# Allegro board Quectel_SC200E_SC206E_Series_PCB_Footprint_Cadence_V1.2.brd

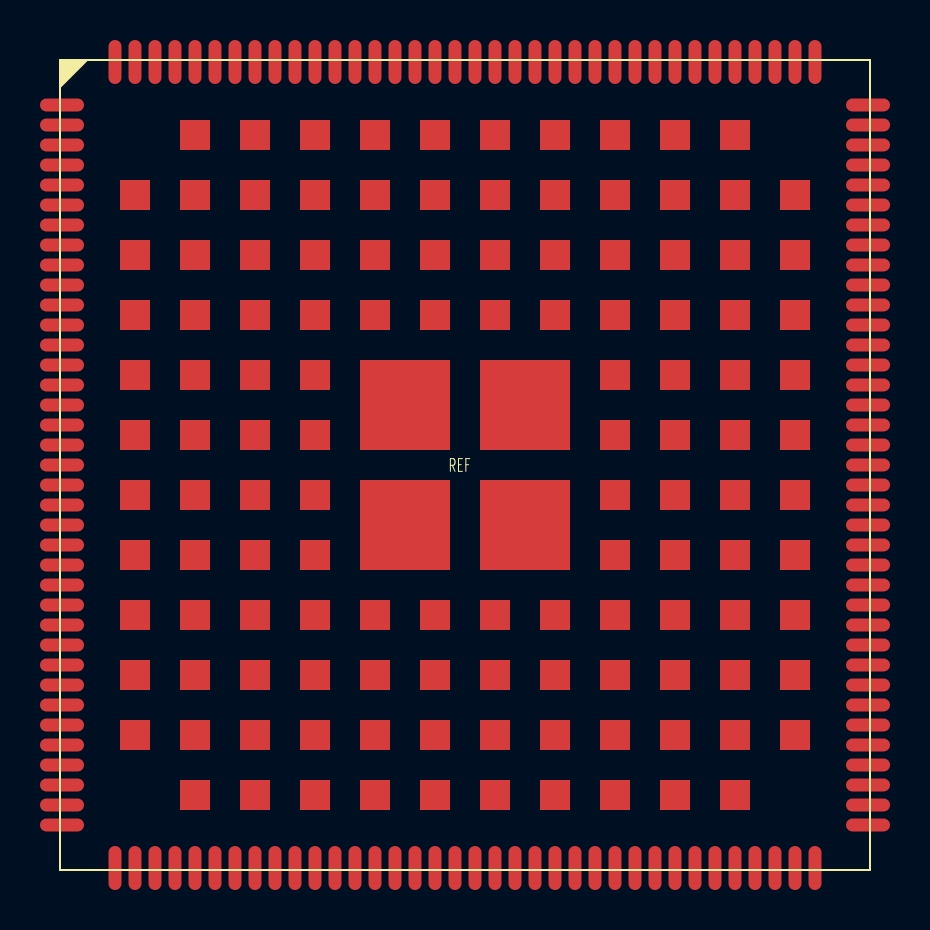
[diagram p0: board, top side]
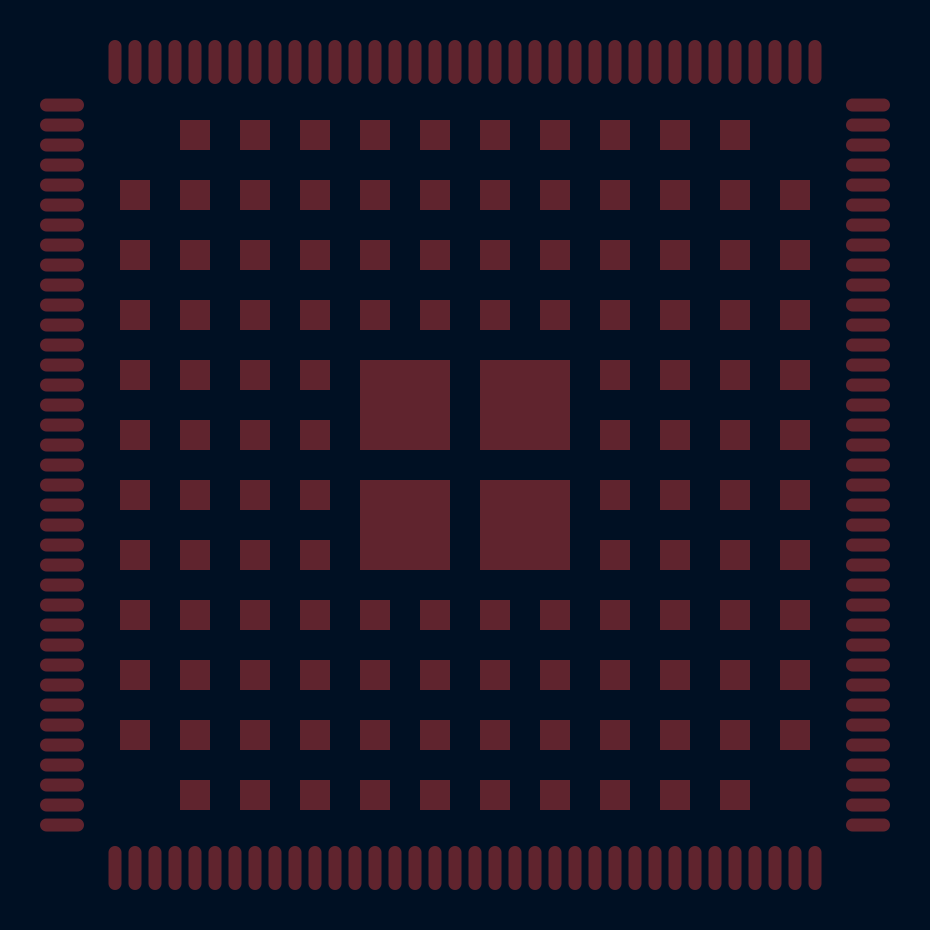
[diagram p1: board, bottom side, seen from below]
No outline. copper layers: TOP, INNER LAYER 2, INNER LAYER 3, BOTTOM. Coordinates in mm from the lowest, leftmost part position.

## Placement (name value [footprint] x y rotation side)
REF  -  [unnamed]  0 0 0 top

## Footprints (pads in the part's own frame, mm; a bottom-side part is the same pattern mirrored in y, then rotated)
unnamed
  oval 2.2x0.65 smd: 1(-20.15,18) 2(-20.15,17) 3(-20.15,16) 4(-20.15,15) 5(-20.15,14) 6(-20.15,13) 7(-20.15,12) 8(-20.15,11) 9(-20.15,10) 10(-20.15,9) 11(-20.15,8) 12(-20.15,7) 13(-20.15,6) 14(-20.15,5) 15(-20.15,4) 16(-20.15,3) 17(-20.15,2) 18(-20.15,1) 19(-20.15,0) 20(-20.15,-1) 21(-20.15,-2) 22(-20.15,-3) 23(-20.15,-4) 24(-20.15,-5) 25(-20.15,-6) 26(-20.15,-7) 27(-20.15,-8) 28(-20.15,-9) 29(-20.15,-10) 30(-20.15,-11) 31(-20.15,-12) 32(-20.15,-13) 33(-20.15,-14) 34(-20.15,-15) 35(-20.15,-16) 36(-20.15,-17) 37(-20.15,-18) 74(20.15,-18) 75(20.15,-17) 76(20.15,-16) 77(20.15,-15) 78(20.15,-14) 79(20.15,-13) 80(20.15,-12) 81(20.15,-11) 82(20.15,-10) 83(20.15,-9) 84(20.15,-8) 85(20.15,-7) 86(20.15,-6) 87(20.15,-5) 88(20.15,-4) 89(20.15,-3) 90(20.15,-2) 91(20.15,-1) 92(20.15,0) 93(20.15,1) 94(20.15,2) 95(20.15,3) 96(20.15,4) 97(20.15,5) 98(20.15,6) 99(20.15,7) 100(20.15,8) 101(20.15,9) 102(20.15,10) 103(20.15,11) 104(20.15,12) 105(20.15,13) 106(20.15,14) 107(20.15,15) 108(20.15,16) 109(20.15,17) 110(20.15,18)
  oval 0.65x2.2 smd: 38(-17.5,-20.15) 39(-16.5,-20.15) 40(-15.5,-20.15) 41(-14.5,-20.15) 42(-13.5,-20.15) 43(-12.5,-20.15) 44(-11.5,-20.15) 45(-10.5,-20.15) 46(-9.5,-20.15) 47(-8.5,-20.15) 48(-7.5,-20.15) 49(-6.5,-20.15) 50(-5.5,-20.15) 51(-4.5,-20.15) 52(-3.5,-20.15) 53(-2.5,-20.15) 54(-1.5,-20.15) 55(-0.5,-20.15) 56(0.5,-20.15) 57(1.5,-20.15) 58(2.5,-20.15) 59(3.5,-20.15) 60(4.5,-20.15) 61(5.5,-20.15) 62(6.5,-20.15) 63(7.5,-20.15) 64(8.5,-20.15) 65(9.5,-20.15) 66(10.5,-20.15) 67(11.5,-20.15) 68(12.5,-20.15) 69(13.5,-20.15) 70(14.5,-20.15) 71(15.5,-20.15) 72(16.5,-20.15) 73(17.5,-20.15) 111(17.5,20.15) 112(16.5,20.15) 113(15.5,20.15) 114(14.5,20.15) 115(13.5,20.15) 116(12.5,20.15) 117(11.5,20.15) 118(10.5,20.15) 119(9.5,20.15) 120(8.5,20.15) 121(7.5,20.15) 122(6.5,20.15) 123(5.5,20.15) 124(4.5,20.15) 125(3.5,20.15) 126(2.5,20.15) 127(1.5,20.15) 128(0.5,20.15) 129(-0.5,20.15) 130(-1.5,20.15) 131(-2.5,20.15) 132(-3.5,20.15) 133(-4.5,20.15) 134(-5.5,20.15) 135(-6.5,20.15) 136(-7.5,20.15) 137(-8.5,20.15) 138(-9.5,20.15) 139(-10.5,20.15) 140(-11.5,20.15) 141(-12.5,20.15) 142(-13.5,20.15) 143(-14.5,20.15) 144(-15.5,20.15) 145(-16.5,20.15) 146(-17.5,20.15)
  rect 1.5x1.5 smd: 147(-16.5,13.5) 148(-16.5,10.5) 149(-16.5,7.5) 150(-16.5,4.5) 151(-16.5,1.5) 152(-16.5,-1.5) 153(-16.5,-4.5) 154(-16.5,-7.5) 155(-16.5,-10.5) 156(-16.5,-13.5) 157(-13.5,-16.5) 158(-10.5,-16.5) 159(-7.5,-16.5) 160(-4.5,-16.5) 161(-1.5,-16.5) 162(1.5,-16.5) 163(4.5,-16.5) 164(7.5,-16.5) 165(10.5,-16.5) 166(13.5,-16.5) 167(16.5,-13.5) 168(16.5,-10.5) 169(16.5,-7.5) 170(16.5,-4.5) 171(16.5,-1.5) 172(16.5,1.5) 173(16.5,4.5) 174(16.5,7.5) 175(16.5,10.5) 176(16.5,13.5) 177(13.5,16.5) 178(10.5,16.5) 179(7.5,16.5) 180(4.5,16.5) 181(1.5,16.5) 182(-1.5,16.5) 183(-4.5,16.5) 184(-7.5,16.5) 185(-10.5,16.5) 186(-13.5,16.5) 187(-13.5,13.5) 188(-13.5,10.5) 189(-13.5,7.5) 190(-13.5,4.5) 191(-13.5,1.5) 192(-13.5,-1.5) 193(-13.5,-4.5) 194(-13.5,-7.5) 195(-13.5,-10.5) 196(-13.5,-13.5) 197(-10.5,-13.5) 198(-7.5,-13.5) 199(-4.5,-13.5) 200(-1.5,-13.5) 201(1.5,-13.5) 202(4.5,-13.5) 203(7.5,-13.5) 204(10.5,-13.5) 205(13.5,-13.5) 206(13.5,-10.5) 207(13.5,-7.5) 208(13.5,-4.5) 209(13.5,-1.5) 210(13.5,1.5) 211(13.5,4.5) 212(13.5,7.5) 213(13.5,10.5) 214(13.5,13.5) 215(10.5,13.5) 216(7.5,13.5) 217(4.5,13.5) 218(1.5,13.5) 219(-1.5,13.5) 220(-4.5,13.5) 221(-7.5,13.5) 222(-10.5,13.5) 223(-10.5,10.5) 224(-10.5,7.5) 225(-10.5,4.5) 226(-10.5,1.5) 227(-10.5,-1.5) 228(-10.5,-4.5) 229(-10.5,-7.5) 230(-10.5,-10.5) 231(-7.5,-10.5) 232(-4.5,-10.5) 233(-1.5,-10.5) 234(1.5,-10.5) 235(4.5,-10.5) 236(7.5,-10.5) 237(10.5,-10.5) 238(10.5,-7.5) 239(10.5,-4.5) 240(10.5,-1.5) 241(10.5,1.5) 242(10.5,4.5) 243(10.5,7.5) 244(10.5,10.5) 245(7.5,10.5) 246(4.5,10.5) 247(1.5,10.5) 248(-1.5,10.5) 249(-4.5,10.5) 250(-7.5,10.5) 251(-7.5,7.5) 252(-7.5,4.5) 253(-7.5,1.5) 254(-7.5,-1.5) 255(-7.5,-4.5) 256(-7.5,-7.5) 257(-4.5,-7.5) 258(-1.5,-7.5) 259(1.5,-7.5) 260(4.5,-7.5) 261(7.5,-7.5) 262(7.5,-4.5) 263(7.5,-1.5) 264(7.5,1.5) 265(7.5,4.5) 266(7.5,7.5) 267(4.5,7.5) 268(1.5,7.5) 269(-1.5,7.5) 270(-4.5,7.5)
  rect 4.5x4.5 smd: 271(-3,3) 272(-3,-3) 273(3,-3) 274(3,3)

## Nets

Pads without a net: REF 1 2 3 4 5 6 7 8 9 10 11 12 13 14 15 16 17 18 19 20 21 22 23 24 25 26 27 28 29 30 31 32 33 34 35 36 37 38 39 40 41 42 43 44 45 46 47 48 49 50 51 52 53 54 55 56 57 58 59 60 61 62 63 64 65 66 67 68 69 70 71 72 73 74 75 76 77 78 79 80 81 82 83 84 85 86 87 88 89 90 91 92 93 94 95 96 97 98 99 100 101 102 103 104 105 106 107 108 109 110 111 112 113 114 115 116 117 118 119 120 121 122 123 124 125 126 127 128 129 130 131 132 133 134 135 136 137 138 139 140 141 142 143 144 145 146 147 148 149 150 151 152 153 154 155 156 157 158 159 160 161 162 163 164 165 166 167 168 169 170 171 172 173 174 175 176 177 178 179 180 181 182 183 184 185 186 187 188 189 190 191 192 193 194 195 196 197 198 199 200 201 202 203 204 205 206 207 208 209 210 211 212 213 214 215 216 217 218 219 220 221 222 223 224 225 226 227 228 229 230 231 232 233 234 235 236 237 238 239 240 241 242 243 244 245 246 247 248 249 250 251 252 253 254 255 256 257 258 259 260 261 262 263 264 265 266 267 268 269 270 271 272 273 274
